VERSION 5.7 ;
  NOWIREEXTENSIONATPIN ON ;
  DIVIDERCHAR "/" ;
  BUSBITCHARS "[]" ;
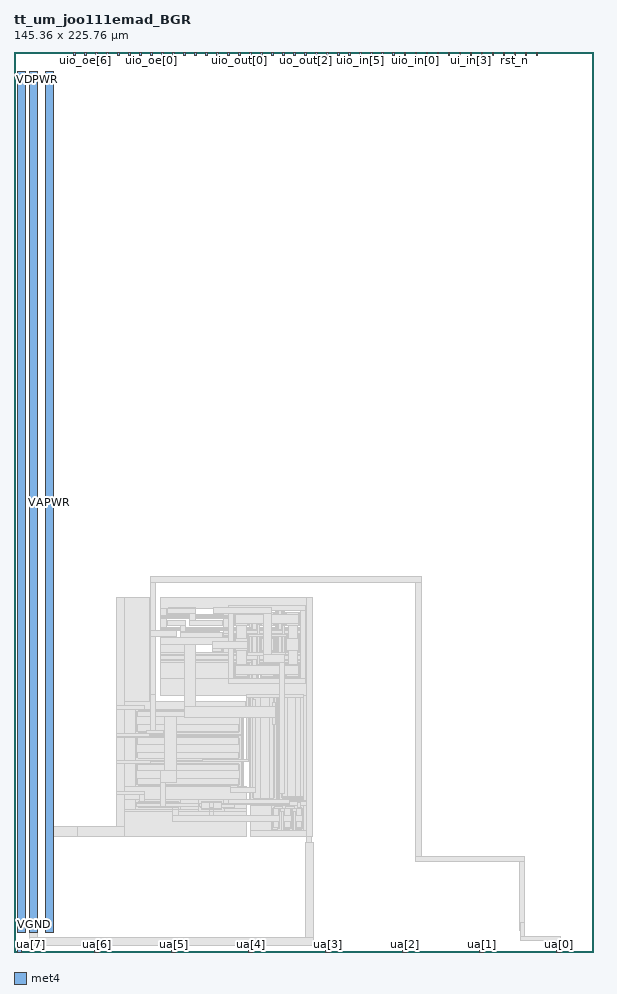
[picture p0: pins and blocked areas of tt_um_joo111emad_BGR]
MACRO tt_um_joo111emad_BGR
  CLASS BLOCK ;
  FOREIGN tt_um_joo111emad_BGR ;
  ORIGIN 0.000 0.000 ;
  SIZE 145.360 BY 225.760 ;
  PIN clk
    DIRECTION INPUT ;
    USE SIGNAL ;
    PORT
      LAYER met4 ;
        RECT 128.190 224.760 128.490 225.760 ;
    END
  END clk
  PIN ena
    DIRECTION INPUT ;
    USE SIGNAL ;
    PORT
      LAYER met4 ;
        RECT 130.950 224.760 131.250 225.760 ;
    END
  END ena
  PIN rst_n
    DIRECTION INPUT ;
    USE SIGNAL ;
    PORT
      LAYER met4 ;
        RECT 125.430 224.760 125.730 225.760 ;
    END
  END rst_n
  PIN ua[0]
    DIRECTION INOUT ;
    USE SIGNAL ;
    ANTENNAGATEAREA 240.560089 ;
    ANTENNADIFFAREA 265.591095 ;
    PORT
      LAYER met4 ;
        RECT 136.170 0.000 137.070 1.000 ;
    END
  END ua[0]
  PIN ua[1]
    DIRECTION INOUT ;
    USE SIGNAL ;
    PORT
      LAYER met4 ;
        RECT 116.850 0.000 117.750 1.000 ;
    END
  END ua[1]
  PIN ua[2]
    DIRECTION INOUT ;
    USE SIGNAL ;
    PORT
      LAYER met4 ;
        RECT 97.530 0.000 98.430 1.000 ;
    END
  END ua[2]
  PIN ua[3]
    DIRECTION INOUT ;
    USE SIGNAL ;
    PORT
      LAYER met4 ;
        RECT 78.210 0.000 79.110 1.000 ;
    END
  END ua[3]
  PIN ua[4]
    DIRECTION INOUT ;
    USE SIGNAL ;
    PORT
      LAYER met4 ;
        RECT 58.890 0.000 59.790 1.000 ;
    END
  END ua[4]
  PIN ua[5]
    DIRECTION INOUT ;
    USE SIGNAL ;
    PORT
      LAYER met4 ;
        RECT 39.570 0.000 40.470 1.000 ;
    END
  END ua[5]
  PIN ua[6]
    DIRECTION INOUT ;
    USE SIGNAL ;
    PORT
      LAYER met4 ;
        RECT 20.250 0.000 21.150 1.000 ;
    END
  END ua[6]
  PIN ua[7]
    DIRECTION INOUT ;
    USE SIGNAL ;
    PORT
      LAYER met4 ;
        RECT 0.930 0.000 1.830 1.000 ;
    END
  END ua[7]
  PIN ui_in[0]
    DIRECTION INPUT ;
    USE SIGNAL ;
    PORT
      LAYER met4 ;
        RECT 122.670 224.760 122.970 225.760 ;
    END
  END ui_in[0]
  PIN ui_in[1]
    DIRECTION INPUT ;
    USE SIGNAL ;
    PORT
      LAYER met4 ;
        RECT 119.910 224.760 120.210 225.760 ;
    END
  END ui_in[1]
  PIN ui_in[2]
    DIRECTION INPUT ;
    USE SIGNAL ;
    PORT
      LAYER met4 ;
        RECT 117.150 224.760 117.450 225.760 ;
    END
  END ui_in[2]
  PIN ui_in[3]
    DIRECTION INPUT ;
    USE SIGNAL ;
    PORT
      LAYER met4 ;
        RECT 114.390 224.760 114.690 225.760 ;
    END
  END ui_in[3]
  PIN ui_in[4]
    DIRECTION INPUT ;
    USE SIGNAL ;
    PORT
      LAYER met4 ;
        RECT 111.630 224.760 111.930 225.760 ;
    END
  END ui_in[4]
  PIN ui_in[5]
    DIRECTION INPUT ;
    USE SIGNAL ;
    PORT
      LAYER met4 ;
        RECT 108.870 224.760 109.170 225.760 ;
    END
  END ui_in[5]
  PIN ui_in[6]
    DIRECTION INPUT ;
    USE SIGNAL ;
    PORT
      LAYER met4 ;
        RECT 106.110 224.760 106.410 225.760 ;
    END
  END ui_in[6]
  PIN ui_in[7]
    DIRECTION INPUT ;
    USE SIGNAL ;
    PORT
      LAYER met4 ;
        RECT 103.350 224.760 103.650 225.760 ;
    END
  END ui_in[7]
  PIN uio_in[0]
    DIRECTION INPUT ;
    USE SIGNAL ;
    PORT
      LAYER met4 ;
        RECT 100.590 224.760 100.890 225.760 ;
    END
  END uio_in[0]
  PIN uio_in[1]
    DIRECTION INPUT ;
    USE SIGNAL ;
    PORT
      LAYER met4 ;
        RECT 97.830 224.760 98.130 225.760 ;
    END
  END uio_in[1]
  PIN uio_in[2]
    DIRECTION INPUT ;
    USE SIGNAL ;
    PORT
      LAYER met4 ;
        RECT 95.070 224.760 95.370 225.760 ;
    END
  END uio_in[2]
  PIN uio_in[3]
    DIRECTION INPUT ;
    USE SIGNAL ;
    PORT
      LAYER met4 ;
        RECT 92.310 224.760 92.610 225.760 ;
    END
  END uio_in[3]
  PIN uio_in[4]
    DIRECTION INPUT ;
    USE SIGNAL ;
    PORT
      LAYER met4 ;
        RECT 89.550 224.760 89.850 225.760 ;
    END
  END uio_in[4]
  PIN uio_in[5]
    DIRECTION INPUT ;
    USE SIGNAL ;
    PORT
      LAYER met4 ;
        RECT 86.790 224.760 87.090 225.760 ;
    END
  END uio_in[5]
  PIN uio_in[6]
    DIRECTION INPUT ;
    USE SIGNAL ;
    PORT
      LAYER met4 ;
        RECT 84.030 224.760 84.330 225.760 ;
    END
  END uio_in[6]
  PIN uio_in[7]
    DIRECTION INPUT ;
    USE SIGNAL ;
    PORT
      LAYER met4 ;
        RECT 81.270 224.760 81.570 225.760 ;
    END
  END uio_in[7]
  PIN uio_oe[0]
    DIRECTION OUTPUT ;
    USE SIGNAL ;
    PORT
      LAYER met4 ;
        RECT 34.350 224.760 34.650 225.760 ;
    END
  END uio_oe[0]
  PIN uio_oe[1]
    DIRECTION OUTPUT ;
    USE SIGNAL ;
    PORT
      LAYER met4 ;
        RECT 31.590 224.760 31.890 225.760 ;
    END
  END uio_oe[1]
  PIN uio_oe[2]
    DIRECTION OUTPUT ;
    USE SIGNAL ;
    PORT
      LAYER met4 ;
        RECT 28.830 224.760 29.130 225.760 ;
    END
  END uio_oe[2]
  PIN uio_oe[3]
    DIRECTION OUTPUT ;
    USE SIGNAL ;
    PORT
      LAYER met4 ;
        RECT 26.070 224.760 26.370 225.760 ;
    END
  END uio_oe[3]
  PIN uio_oe[4]
    DIRECTION OUTPUT ;
    USE SIGNAL ;
    PORT
      LAYER met4 ;
        RECT 23.310 224.760 23.610 225.760 ;
    END
  END uio_oe[4]
  PIN uio_oe[5]
    DIRECTION OUTPUT ;
    USE SIGNAL ;
    PORT
      LAYER met4 ;
        RECT 20.550 224.760 20.850 225.760 ;
    END
  END uio_oe[5]
  PIN uio_oe[6]
    DIRECTION OUTPUT ;
    USE SIGNAL ;
    PORT
      LAYER met4 ;
        RECT 17.790 224.760 18.090 225.760 ;
    END
  END uio_oe[6]
  PIN uio_oe[7]
    DIRECTION OUTPUT ;
    USE SIGNAL ;
    PORT
      LAYER met4 ;
        RECT 15.030 224.760 15.330 225.760 ;
    END
  END uio_oe[7]
  PIN uio_out[0]
    DIRECTION OUTPUT ;
    USE SIGNAL ;
    PORT
      LAYER met4 ;
        RECT 56.430 224.760 56.730 225.760 ;
    END
  END uio_out[0]
  PIN uio_out[1]
    DIRECTION OUTPUT ;
    USE SIGNAL ;
    PORT
      LAYER met4 ;
        RECT 53.670 224.760 53.970 225.760 ;
    END
  END uio_out[1]
  PIN uio_out[2]
    DIRECTION OUTPUT ;
    USE SIGNAL ;
    PORT
      LAYER met4 ;
        RECT 50.910 224.760 51.210 225.760 ;
    END
  END uio_out[2]
  PIN uio_out[3]
    DIRECTION OUTPUT ;
    USE SIGNAL ;
    PORT
      LAYER met4 ;
        RECT 48.150 224.760 48.450 225.760 ;
    END
  END uio_out[3]
  PIN uio_out[4]
    DIRECTION OUTPUT ;
    USE SIGNAL ;
    PORT
      LAYER met4 ;
        RECT 45.390 224.760 45.690 225.760 ;
    END
  END uio_out[4]
  PIN uio_out[5]
    DIRECTION OUTPUT ;
    USE SIGNAL ;
    PORT
      LAYER met4 ;
        RECT 42.630 224.760 42.930 225.760 ;
    END
  END uio_out[5]
  PIN uio_out[6]
    DIRECTION OUTPUT ;
    USE SIGNAL ;
    PORT
      LAYER met4 ;
        RECT 39.870 224.760 40.170 225.760 ;
    END
  END uio_out[6]
  PIN uio_out[7]
    DIRECTION OUTPUT ;
    USE SIGNAL ;
    PORT
      LAYER met4 ;
        RECT 37.110 224.760 37.410 225.760 ;
    END
  END uio_out[7]
  PIN uo_out[0]
    DIRECTION OUTPUT ;
    USE SIGNAL ;
    PORT
      LAYER met4 ;
        RECT 78.510 224.760 78.810 225.760 ;
    END
  END uo_out[0]
  PIN uo_out[1]
    DIRECTION OUTPUT ;
    USE SIGNAL ;
    PORT
      LAYER met4 ;
        RECT 75.750 224.760 76.050 225.760 ;
    END
  END uo_out[1]
  PIN uo_out[2]
    DIRECTION OUTPUT ;
    USE SIGNAL ;
    PORT
      LAYER met4 ;
        RECT 72.990 224.760 73.290 225.760 ;
    END
  END uo_out[2]
  PIN uo_out[3]
    DIRECTION OUTPUT ;
    USE SIGNAL ;
    PORT
      LAYER met4 ;
        RECT 70.230 224.760 70.530 225.760 ;
    END
  END uo_out[3]
  PIN uo_out[4]
    DIRECTION OUTPUT ;
    USE SIGNAL ;
    PORT
      LAYER met4 ;
        RECT 67.470 224.760 67.770 225.760 ;
    END
  END uo_out[4]
  PIN uo_out[5]
    DIRECTION OUTPUT ;
    USE SIGNAL ;
    PORT
      LAYER met4 ;
        RECT 64.710 224.760 65.010 225.760 ;
    END
  END uo_out[5]
  PIN uo_out[6]
    DIRECTION OUTPUT ;
    USE SIGNAL ;
    PORT
      LAYER met4 ;
        RECT 61.950 224.760 62.250 225.760 ;
    END
  END uo_out[6]
  PIN uo_out[7]
    DIRECTION OUTPUT ;
    USE SIGNAL ;
    PORT
      LAYER met4 ;
        RECT 59.190 224.760 59.490 225.760 ;
    END
  END uo_out[7]
  PIN VDPWR
    DIRECTION INOUT ;
    USE POWER ;
    PORT
      LAYER met4 ;
        RECT 1.000 5.000 3.000 220.760 ;
    END
  END VDPWR
  PIN VGND
    DIRECTION INOUT ;
    USE GROUND ;
    PORT
      LAYER met4 ;
        RECT 4.000 5.000 6.000 220.760 ;
    END
  END VGND
  PIN VAPWR
    DIRECTION INOUT ;
    USE POWER ;
    PORT
      LAYER met4 ;
        RECT 7.900 5.000 9.900 220.760 ;
    END
  END VAPWR
  OBS
      LAYER pwell ;
        RECT 37.710 86.680 53.030 87.110 ;
        RECT 37.710 84.570 38.140 86.680 ;
        RECT 52.600 84.570 53.030 86.680 ;
        RECT 37.710 84.140 53.030 84.570 ;
        RECT 53.720 86.125 73.300 86.890 ;
        RECT 37.710 83.590 53.030 84.020 ;
        RECT 37.710 81.480 38.140 83.590 ;
        RECT 52.600 81.480 53.030 83.590 ;
        RECT 37.710 81.050 53.030 81.480 ;
        RECT 37.710 80.600 53.030 81.030 ;
        RECT 37.710 78.490 38.140 80.600 ;
        RECT 52.600 78.490 53.030 80.600 ;
        RECT 37.710 78.060 53.030 78.490 ;
        RECT 53.720 80.955 54.485 86.125 ;
        RECT 59.655 80.955 60.925 86.125 ;
        RECT 66.095 80.955 67.365 86.125 ;
        RECT 72.535 80.955 73.300 86.125 ;
        RECT 53.720 79.685 73.300 80.955 ;
        RECT 42.170 77.160 52.830 77.590 ;
        RECT 42.170 75.050 42.600 77.160 ;
        RECT 52.400 75.050 52.830 77.160 ;
        RECT 42.170 74.620 52.830 75.050 ;
        RECT 53.720 74.515 54.485 79.685 ;
        RECT 59.655 74.515 60.925 79.685 ;
        RECT 66.095 74.515 67.365 79.685 ;
        RECT 72.535 74.515 73.300 79.685 ;
        RECT 53.720 74.010 73.300 74.515 ;
        RECT 53.710 73.750 73.300 74.010 ;
        RECT 53.710 73.245 73.290 73.750 ;
        RECT 53.710 68.075 54.475 73.245 ;
        RECT 59.645 68.075 60.915 73.245 ;
        RECT 66.085 68.075 67.355 73.245 ;
        RECT 72.525 68.075 73.290 73.245 ;
        RECT 53.710 67.310 73.290 68.075 ;
      LAYER nwell ;
        RECT 29.710 40.760 57.680 61.600 ;
        RECT 29.760 35.170 42.730 38.750 ;
        RECT 45.800 34.770 53.380 38.740 ;
      LAYER pwell ;
        RECT 59.020 37.510 66.200 64.990 ;
        RECT 66.210 37.510 73.390 64.990 ;
        RECT 63.930 29.960 73.270 37.140 ;
      LAYER li1 ;
        RECT 25.770 62.900 33.870 89.000 ;
        RECT 36.770 86.100 74.770 89.000 ;
        RECT 36.770 84.440 38.220 86.100 ;
        RECT 38.490 84.920 40.650 86.100 ;
        RECT 50.090 84.920 52.250 86.100 ;
        RECT 52.520 85.600 74.770 86.100 ;
        RECT 52.520 85.585 59.475 85.600 ;
        RECT 52.520 84.440 55.070 85.585 ;
        RECT 36.770 84.270 55.070 84.440 ;
        RECT 36.770 83.890 38.220 84.270 ;
        RECT 52.520 83.890 55.070 84.270 ;
        RECT 36.770 83.720 55.070 83.890 ;
        RECT 36.770 81.350 38.220 83.720 ;
        RECT 38.490 81.830 40.650 83.240 ;
        RECT 50.090 81.830 52.250 83.240 ;
        RECT 52.520 81.495 55.070 83.720 ;
        RECT 55.335 81.805 58.805 85.275 ;
        RECT 59.115 81.495 59.475 85.585 ;
        RECT 52.520 81.350 59.475 81.495 ;
        RECT 36.770 81.180 59.475 81.350 ;
        RECT 36.770 80.900 38.220 81.180 ;
        RECT 52.520 81.135 59.475 81.180 ;
        RECT 52.520 80.900 55.070 81.135 ;
        RECT 36.770 80.815 55.070 80.900 ;
        RECT 59.795 80.815 60.785 85.600 ;
        RECT 61.105 85.585 65.915 85.600 ;
        RECT 61.105 82.050 61.465 85.585 ;
        RECT 61.070 81.495 61.470 82.050 ;
        RECT 61.775 81.805 65.245 85.275 ;
        RECT 65.555 81.495 65.915 85.585 ;
        RECT 61.070 81.135 65.915 81.495 ;
        RECT 61.070 80.815 61.470 81.135 ;
        RECT 66.235 80.815 67.225 85.600 ;
        RECT 67.545 85.585 74.770 85.600 ;
        RECT 67.545 81.950 67.905 85.585 ;
        RECT 67.520 81.495 67.905 81.950 ;
        RECT 68.215 81.805 71.685 85.275 ;
        RECT 71.920 81.495 74.770 85.585 ;
        RECT 67.520 81.135 74.770 81.495 ;
        RECT 67.520 80.815 67.870 81.135 ;
        RECT 71.920 80.815 74.770 81.135 ;
        RECT 36.770 80.730 74.770 80.815 ;
        RECT 36.770 78.900 38.220 80.730 ;
        RECT 38.490 78.900 40.650 80.250 ;
        RECT 50.090 78.900 52.250 80.250 ;
        RECT 52.520 79.825 74.770 80.730 ;
        RECT 52.520 79.505 55.070 79.825 ;
        RECT 52.520 79.500 59.475 79.505 ;
        RECT 59.795 79.500 60.785 79.825 ;
        RECT 61.070 79.505 61.470 79.825 ;
        RECT 61.070 79.500 65.915 79.505 ;
        RECT 66.235 79.500 67.225 79.825 ;
        RECT 67.520 79.505 67.870 79.825 ;
        RECT 71.920 79.505 74.770 79.825 ;
        RECT 67.520 79.500 74.770 79.505 ;
        RECT 52.520 79.145 74.770 79.500 ;
        RECT 52.520 78.900 55.070 79.145 ;
        RECT 58.620 79.100 68.320 79.145 ;
        RECT 36.770 77.050 55.070 78.900 ;
        RECT 36.770 75.100 42.720 77.050 ;
        RECT 42.950 75.400 45.110 76.810 ;
        RECT 49.890 75.400 52.050 76.810 ;
        RECT 52.520 75.100 55.070 77.050 ;
        RECT 55.335 75.365 58.805 78.835 ;
        RECT 36.770 75.055 55.070 75.100 ;
        RECT 59.115 75.055 59.475 79.100 ;
        RECT 36.770 75.050 59.475 75.055 ;
        RECT 59.795 75.050 60.785 79.100 ;
        RECT 61.070 75.055 61.470 79.100 ;
        RECT 61.775 75.365 65.245 78.835 ;
        RECT 65.555 75.055 65.915 79.100 ;
        RECT 61.070 75.050 65.915 75.055 ;
        RECT 66.235 75.050 67.225 79.100 ;
        RECT 67.520 75.055 67.905 79.100 ;
        RECT 68.215 75.365 71.685 78.835 ;
        RECT 71.920 75.055 74.770 79.145 ;
        RECT 67.520 75.050 74.770 75.055 ;
        RECT 36.770 74.695 74.770 75.050 ;
        RECT 36.770 74.375 55.070 74.695 ;
        RECT 58.620 74.650 68.220 74.695 ;
        RECT 59.795 74.375 60.785 74.650 ;
        RECT 61.070 74.375 61.470 74.650 ;
        RECT 66.235 74.375 67.225 74.650 ;
        RECT 67.520 74.375 67.870 74.650 ;
        RECT 71.920 74.375 74.770 74.695 ;
        RECT 36.770 73.385 74.770 74.375 ;
        RECT 36.770 73.065 55.070 73.385 ;
        RECT 36.770 72.705 59.465 73.065 ;
        RECT 36.770 68.615 55.070 72.705 ;
        RECT 55.325 68.925 58.795 72.395 ;
        RECT 59.105 68.615 59.465 72.705 ;
        RECT 36.770 68.500 59.465 68.615 ;
        RECT 59.785 68.500 60.775 73.385 ;
        RECT 61.070 73.065 61.470 73.385 ;
        RECT 61.070 72.705 65.905 73.065 ;
        RECT 61.070 72.150 61.470 72.705 ;
        RECT 61.095 68.615 61.455 72.150 ;
        RECT 61.765 68.925 65.235 72.395 ;
        RECT 65.545 68.615 65.905 72.705 ;
        RECT 61.095 68.500 65.905 68.615 ;
        RECT 66.225 68.500 67.215 73.385 ;
        RECT 67.520 73.065 67.870 73.385 ;
        RECT 71.920 73.065 74.770 73.385 ;
        RECT 67.520 72.705 74.770 73.065 ;
        RECT 67.520 72.350 67.895 72.705 ;
        RECT 67.535 68.615 67.895 72.350 ;
        RECT 68.205 68.925 71.675 72.395 ;
        RECT 71.920 68.615 74.770 72.705 ;
        RECT 67.535 68.500 74.770 68.615 ;
        RECT 36.770 64.350 74.770 68.500 ;
        RECT 36.770 64.300 52.520 64.350 ;
        RECT 25.770 60.900 58.170 62.900 ;
        RECT 25.770 54.580 30.520 60.900 ;
        RECT 31.175 60.370 56.215 60.540 ;
        RECT 30.790 55.310 30.960 60.310 ;
        RECT 56.430 55.310 56.600 60.310 ;
        RECT 31.175 55.080 56.215 55.250 ;
        RECT 57.120 54.580 57.290 60.900 ;
        RECT 25.770 54.410 57.290 54.580 ;
        RECT 25.770 47.950 30.520 54.410 ;
        RECT 31.175 53.740 56.215 53.910 ;
        RECT 30.790 48.680 30.960 53.680 ;
        RECT 56.430 48.680 56.600 53.680 ;
        RECT 31.175 48.450 56.215 48.620 ;
        RECT 57.120 47.950 57.290 54.410 ;
        RECT 25.770 47.780 57.290 47.950 ;
        RECT 25.770 41.450 30.520 47.780 ;
        RECT 31.175 47.110 56.215 47.280 ;
        RECT 30.790 42.050 30.960 47.050 ;
        RECT 56.430 42.050 56.600 47.050 ;
        RECT 31.175 41.820 56.215 41.990 ;
        RECT 57.120 41.450 57.290 47.780 ;
        RECT 25.770 38.150 58.220 41.450 ;
        RECT 25.770 38.130 46.400 38.150 ;
        RECT 25.770 35.810 30.520 38.130 ;
        RECT 31.225 37.520 41.265 37.690 ;
        RECT 30.840 36.460 31.010 37.460 ;
        RECT 41.480 36.460 41.650 37.460 ;
        RECT 31.225 36.230 41.265 36.400 ;
        RECT 41.820 35.810 46.400 38.130 ;
        RECT 47.090 37.490 52.090 37.660 ;
        RECT 46.860 36.235 47.030 37.275 ;
        RECT 52.150 36.235 52.320 37.275 ;
        RECT 47.090 35.850 52.090 36.020 ;
        RECT 52.620 35.910 58.220 38.150 ;
        RECT 59.210 38.000 59.380 64.350 ;
        RECT 60.110 63.940 65.110 64.110 ;
        RECT 59.880 38.730 60.050 63.770 ;
        RECT 65.170 38.730 65.340 63.770 ;
        RECT 60.110 38.390 65.110 38.560 ;
        RECT 65.840 38.000 66.010 64.350 ;
        RECT 66.400 38.000 66.570 64.350 ;
        RECT 67.300 63.940 72.300 64.110 ;
        RECT 67.070 38.730 67.240 63.770 ;
        RECT 72.360 38.730 72.530 63.770 ;
        RECT 67.300 38.390 72.300 38.560 ;
        RECT 72.720 38.000 74.770 64.350 ;
        RECT 59.210 37.700 74.770 38.000 ;
        RECT 25.770 35.360 46.400 35.810 ;
        RECT 52.820 35.360 58.220 35.910 ;
        RECT 25.770 29.050 58.220 35.360 ;
        RECT 59.270 36.650 74.770 37.700 ;
        RECT 59.270 30.500 64.520 36.650 ;
        RECT 65.150 36.110 66.190 36.280 ;
        RECT 64.810 31.050 64.980 36.050 ;
        RECT 66.360 31.050 66.530 36.050 ;
        RECT 65.150 30.820 66.190 30.990 ;
        RECT 67.050 30.500 67.220 36.650 ;
        RECT 68.080 36.110 69.120 36.280 ;
        RECT 67.740 31.050 67.910 36.050 ;
        RECT 69.290 31.050 69.460 36.050 ;
        RECT 68.080 30.820 69.120 30.990 ;
        RECT 69.980 30.500 70.150 36.650 ;
        RECT 71.010 36.110 72.050 36.280 ;
        RECT 70.670 31.050 70.840 36.050 ;
        RECT 72.220 31.050 72.390 36.050 ;
        RECT 71.010 30.820 72.050 30.990 ;
        RECT 72.720 30.500 74.770 36.650 ;
        RECT 59.270 29.050 74.770 30.500 ;
      LAYER met1 ;
        RECT 34.270 92.790 102.110 94.090 ;
        RECT 25.770 61.900 27.770 89.000 ;
        RECT 34.270 80.650 35.570 92.790 ;
        RECT 38.720 86.280 45.470 86.320 ;
        RECT 50.140 86.280 52.100 86.330 ;
        RECT 38.520 84.970 45.470 86.280 ;
        RECT 50.115 84.970 52.220 86.280 ;
        RECT 53.720 85.600 73.020 86.850 ;
        RECT 38.720 84.920 45.470 84.970 ;
        RECT 38.920 83.190 43.120 83.250 ;
        RECT 38.520 81.880 43.120 83.190 ;
        RECT 38.920 81.850 43.120 81.880 ;
        RECT 44.070 83.150 45.470 84.920 ;
        RECT 50.140 84.830 52.100 84.970 ;
        RECT 50.115 83.150 52.220 83.190 ;
        RECT 44.070 81.880 52.220 83.150 ;
        RECT 44.070 81.850 51.570 81.880 ;
        RECT 34.270 79.200 40.720 80.650 ;
        RECT 41.870 80.300 43.120 81.850 ;
        RECT 41.870 80.200 51.520 80.300 ;
        RECT 34.270 62.850 35.570 79.200 ;
        RECT 38.520 78.890 40.625 79.200 ;
        RECT 41.870 78.890 52.220 80.200 ;
        RECT 41.870 78.850 51.520 78.890 ;
        RECT 42.870 75.300 45.120 76.900 ;
        RECT 49.870 75.350 52.020 77.900 ;
        RECT 53.720 68.600 55.070 85.600 ;
        RECT 55.545 84.650 58.595 85.065 ;
        RECT 61.985 84.650 65.035 85.065 ;
        RECT 68.425 84.650 71.475 85.065 ;
        RECT 55.545 82.400 71.475 84.650 ;
        RECT 55.545 82.015 58.595 82.400 ;
        RECT 55.920 78.625 58.220 82.015 ;
        RECT 61.070 79.550 61.470 82.050 ;
        RECT 61.985 82.015 65.035 82.400 ;
        RECT 68.425 82.015 71.475 82.400 ;
        RECT 67.420 79.550 67.870 81.950 ;
        RECT 58.720 79.050 68.270 79.550 ;
        RECT 55.545 75.575 58.595 78.625 ;
        RECT 55.920 72.185 58.220 75.575 ;
        RECT 61.070 75.050 61.470 79.050 ;
        RECT 61.985 75.575 65.035 78.625 ;
        RECT 67.420 75.050 67.870 79.050 ;
        RECT 68.770 78.625 71.020 82.015 ;
        RECT 68.425 75.575 71.475 78.625 ;
        RECT 58.670 74.500 68.120 75.050 ;
        RECT 55.535 71.800 58.585 72.185 ;
        RECT 61.070 72.150 61.470 74.500 ;
        RECT 67.420 72.400 67.870 74.500 ;
        RECT 68.770 72.185 71.020 75.575 ;
        RECT 61.975 71.800 65.025 72.185 ;
        RECT 68.415 71.800 71.465 72.185 ;
        RECT 55.535 69.500 71.465 71.800 ;
        RECT 55.535 69.135 58.585 69.500 ;
        RECT 61.975 69.135 65.025 69.500 ;
        RECT 68.415 69.135 71.465 69.500 ;
        RECT 71.820 68.600 73.020 85.600 ;
        RECT 53.720 67.300 73.020 68.600 ;
        RECT 53.770 67.250 73.020 67.300 ;
        RECT 58.220 63.900 72.520 64.550 ;
        RECT 25.770 60.900 32.770 61.900 ;
        RECT 25.770 54.750 27.770 60.900 ;
        RECT 31.720 60.570 32.770 60.900 ;
        RECT 31.195 60.340 56.195 60.570 ;
        RECT 31.720 60.300 32.770 60.340 ;
        RECT 30.760 59.000 30.990 60.290 ;
        RECT 56.400 59.000 56.630 60.290 ;
        RECT 30.760 56.950 56.630 59.000 ;
        RECT 30.760 55.330 30.990 56.950 ;
        RECT 33.320 55.280 37.520 55.450 ;
        RECT 56.400 55.330 56.630 56.950 ;
        RECT 31.195 55.050 56.195 55.280 ;
        RECT 33.320 54.900 37.520 55.050 ;
        RECT 25.770 53.940 33.920 54.750 ;
        RECT 25.770 53.900 56.195 53.940 ;
        RECT 25.770 48.150 27.770 53.900 ;
        RECT 31.195 53.710 56.195 53.900 ;
        RECT 31.720 53.700 33.920 53.710 ;
        RECT 30.760 52.150 30.990 53.660 ;
        RECT 56.400 52.150 56.630 53.660 ;
        RECT 30.670 50.100 56.630 52.150 ;
        RECT 30.760 48.700 30.990 50.100 ;
        RECT 56.400 48.700 56.630 50.100 ;
        RECT 31.195 48.600 56.195 48.650 ;
        RECT 31.195 48.420 56.270 48.600 ;
        RECT 47.220 48.350 56.270 48.420 ;
        RECT 58.220 48.350 58.870 63.900 ;
        RECT 25.770 47.310 34.220 48.150 ;
        RECT 47.220 47.700 58.870 48.350 ;
        RECT 59.850 63.450 60.080 63.750 ;
        RECT 25.770 47.300 56.195 47.310 ;
        RECT 25.770 40.350 27.770 47.300 ;
        RECT 31.195 47.080 56.195 47.300 ;
        RECT 30.760 45.550 30.990 47.030 ;
        RECT 56.400 45.550 56.630 47.030 ;
        RECT 30.760 43.500 56.630 45.550 ;
        RECT 30.760 42.070 30.990 43.500 ;
        RECT 56.400 42.070 56.630 43.500 ;
        RECT 31.195 41.790 56.195 42.020 ;
        RECT 54.370 41.200 56.120 41.790 ;
        RECT 59.850 41.200 60.670 63.450 ;
        RECT 25.770 39.400 32.820 40.350 ;
        RECT 54.370 40.100 60.670 41.200 ;
        RECT 55.380 40.090 60.430 40.100 ;
        RECT 25.770 31.400 27.770 39.400 ;
        RECT 31.520 37.720 32.820 39.400 ;
        RECT 59.850 38.750 60.080 40.090 ;
        RECT 61.820 38.590 64.020 63.900 ;
        RECT 65.140 62.550 65.370 63.750 ;
        RECT 67.040 62.950 67.270 63.750 ;
        RECT 64.870 57.000 65.720 62.550 ;
        RECT 65.140 38.750 65.370 57.000 ;
        RECT 66.570 39.850 67.370 62.950 ;
        RECT 67.040 38.750 67.270 39.850 ;
        RECT 68.720 39.060 70.570 63.900 ;
        RECT 67.610 38.950 70.570 39.060 ;
        RECT 71.970 63.750 72.520 63.900 ;
        RECT 71.970 38.950 72.560 63.750 ;
        RECT 67.610 38.750 72.560 38.950 ;
        RECT 67.610 38.590 72.520 38.750 ;
        RECT 60.130 38.360 65.090 38.590 ;
        RECT 67.320 38.360 72.520 38.590 ;
        RECT 61.820 38.200 64.020 38.360 ;
        RECT 67.610 38.200 72.520 38.360 ;
        RECT 31.245 37.490 41.245 37.720 ;
        RECT 47.110 37.460 52.070 37.690 ;
        RECT 30.810 37.200 31.040 37.440 ;
        RECT 41.450 37.200 41.680 37.440 ;
        RECT 46.830 37.200 47.060 37.255 ;
        RECT 30.770 36.600 36.670 37.200 ;
        RECT 36.870 36.750 37.870 37.100 ;
        RECT 38.070 36.600 46.400 37.200 ;
        RECT 46.550 36.600 47.060 37.200 ;
        RECT 30.810 36.480 31.040 36.600 ;
        RECT 41.450 36.480 41.680 36.600 ;
        RECT 39.870 36.430 41.170 36.450 ;
        RECT 31.245 36.200 41.245 36.430 ;
        RECT 46.830 36.255 47.060 36.600 ;
        RECT 39.880 35.810 41.180 36.200 ;
        RECT 49.120 36.190 50.120 37.460 ;
        RECT 53.720 37.300 69.010 38.200 ;
        RECT 52.120 37.100 69.010 37.300 ;
        RECT 52.120 36.250 55.270 37.100 ;
        RECT 65.270 36.310 66.120 36.450 ;
        RECT 49.110 36.050 50.120 36.190 ;
        RECT 65.170 36.080 66.170 36.310 ;
        RECT 47.110 35.820 52.070 36.050 ;
        RECT 39.870 35.800 41.180 35.810 ;
        RECT 39.870 34.300 41.170 35.800 ;
        RECT 49.110 35.230 50.120 35.820 ;
        RECT 64.780 35.800 65.010 36.030 ;
        RECT 65.270 35.900 66.120 36.080 ;
        RECT 49.120 34.300 50.120 35.230 ;
        RECT 39.870 34.250 50.120 34.300 ;
        RECT 64.720 34.250 65.070 35.800 ;
        RECT 66.330 34.250 66.560 36.030 ;
        RECT 66.870 35.900 67.320 36.500 ;
        RECT 68.220 36.310 68.970 36.500 ;
        RECT 68.100 36.080 69.100 36.310 ;
        RECT 67.710 35.900 67.940 36.030 ;
        RECT 68.220 35.900 68.970 36.080 ;
        RECT 66.870 35.150 67.970 35.900 ;
        RECT 39.870 32.850 66.560 34.250 ;
        RECT 12.750 29.000 27.770 31.400 ;
        RECT 64.720 31.300 65.070 32.850 ;
        RECT 64.720 30.800 66.170 31.300 ;
        RECT 66.330 31.070 66.560 32.850 ;
        RECT 67.670 34.250 67.970 35.150 ;
        RECT 69.260 34.250 69.490 36.030 ;
        RECT 69.820 35.900 70.270 36.500 ;
        RECT 71.120 36.310 71.870 37.600 ;
        RECT 71.030 36.080 72.030 36.310 ;
        RECT 70.640 35.900 70.870 36.030 ;
        RECT 71.120 35.900 71.870 36.080 ;
        RECT 69.820 35.150 70.920 35.900 ;
        RECT 67.670 32.850 69.490 34.250 ;
        RECT 67.670 31.300 67.970 32.850 ;
        RECT 67.670 31.020 69.020 31.300 ;
        RECT 69.260 31.070 69.490 32.850 ;
        RECT 70.620 34.250 70.920 35.150 ;
        RECT 72.190 34.250 72.420 36.030 ;
        RECT 70.620 32.850 72.420 34.250 ;
        RECT 70.620 31.300 70.920 32.850 ;
        RECT 70.620 31.020 71.970 31.300 ;
        RECT 72.190 31.070 72.420 32.850 ;
        RECT 67.670 30.800 69.100 31.020 ;
        RECT 70.620 30.800 72.030 31.020 ;
        RECT 65.170 30.790 66.170 30.800 ;
        RECT 68.100 30.790 69.100 30.800 ;
        RECT 71.030 30.790 72.030 30.800 ;
        RECT 73.320 29.050 74.770 89.000 ;
        RECT 73.350 25.800 74.750 29.050 ;
        RECT 100.810 24.010 102.110 92.790 ;
        RECT 100.810 22.710 128.110 24.010 ;
        RECT 126.810 5.290 128.110 22.710 ;
      LAYER met2 ;
        RECT 50.140 84.830 64.570 86.330 ;
        RECT 34.270 55.450 35.570 64.650 ;
        RECT 42.745 61.600 45.495 77.125 ;
        RECT 49.870 76.050 58.470 77.900 ;
        RECT 49.870 75.350 52.020 76.050 ;
        RECT 62.520 74.600 64.570 84.830 ;
        RECT 62.520 72.600 67.870 74.600 ;
        RECT 33.320 54.900 37.520 55.450 ;
        RECT 37.870 45.550 40.820 59.000 ;
        RECT 42.745 58.850 65.670 61.600 ;
        RECT 36.670 42.550 40.820 45.550 ;
        RECT 36.670 36.600 38.070 42.550 ;
        RECT 66.570 39.850 67.870 72.600 ;
        RECT 65.270 35.900 67.320 36.500 ;
        RECT 68.220 35.900 70.270 36.500 ;
        RECT 13.200 29.300 15.500 31.050 ;
        RECT 73.550 25.950 74.550 27.300 ;
        RECT 127.240 5.370 127.800 7.180 ;
      LAYER met3 ;
        RECT 13.150 29.325 15.550 31.025 ;
        RECT 73.500 25.975 74.600 27.275 ;
        RECT 127.190 5.395 127.850 7.155 ;
      LAYER met4 ;
        RECT 9.900 29.000 16.000 31.400 ;
        RECT 4.000 3.600 6.000 5.000 ;
        RECT 73.150 3.600 75.150 27.450 ;
        RECT 4.000 1.600 75.150 3.600 ;
        RECT 127.080 3.810 127.980 7.300 ;
        RECT 127.080 2.910 137.070 3.810 ;
        RECT 136.170 1.000 137.070 2.910 ;
  END
END tt_um_joo111emad_BGR
END LIBRARY

